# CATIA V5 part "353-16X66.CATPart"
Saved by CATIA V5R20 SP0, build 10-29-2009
Part number: 353-16X66
Definition: NONE
Nomenclature: 353-16X66
Source: Unknown
Description: 353-16X66
Bounding box of the stored display mesh (mm): x -5 to 61, y -13 to 13, z -13 to 13
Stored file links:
  C:\Users\Utente\Desktop\IO LAVORO\3D X SITO CF\X SITO\PLASTICA\353\353-16X66.CATPart

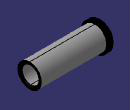
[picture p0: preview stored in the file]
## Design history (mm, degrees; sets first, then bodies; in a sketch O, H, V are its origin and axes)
Body1 "353-16X66" (main body)
  Solid1: solid without history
